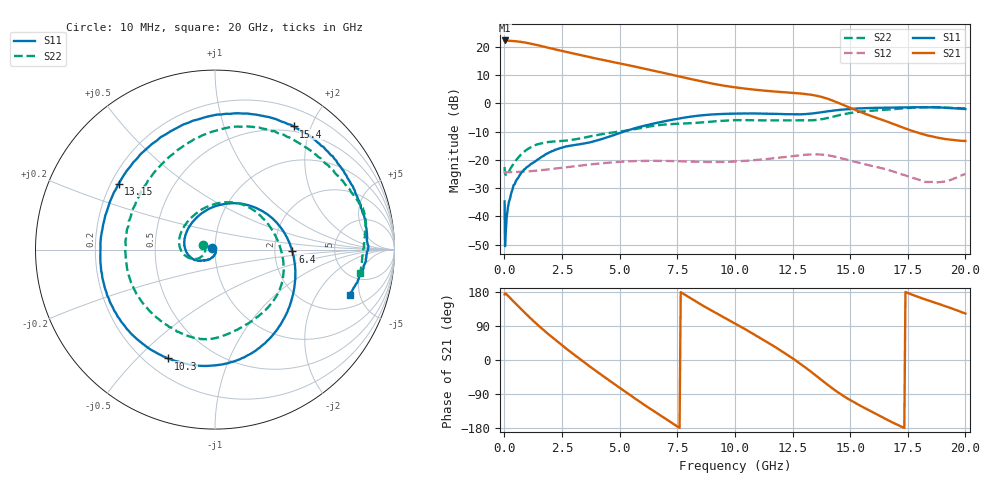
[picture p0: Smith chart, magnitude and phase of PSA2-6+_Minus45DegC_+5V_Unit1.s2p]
!Keysight Technologies,N5242A,MY47200155,A.10.49.08
!Date: Thursday, October 19, 2023 15:29:46
!Correction: S11(Full 2 Port(1,2))
!S21(Full 2 Port(1,2))
!S12(Full 2 Port(1,2))
!S22(Full 2 Port(1,2))
!S2P File: Measurements: S11, S21, S12, S22:
# Hz S  dB  R 50
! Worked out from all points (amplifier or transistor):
!   408 points, 10 MHz to 20 GHz, reference 50 ohm
!   highest |S21| = 22.3 dB at 10 MHz (marker M1)
!   |S21| within 3 dB of that: start of sweep to 2.122 GHz
!   unconditionally stable (mu >= 1): start of sweep to end of sweep
!   at 3.05 GHz: K = 1.05, MAG = 18.5 dB, |S12| = -22.3 dB
!   at 9.85 GHz: K = 1.15, MAG = 10.9 dB, |S12| = -20.7 dB
!   at 20 GHz: K = 4.61, MAG = -3.8 dB, |S12| = -25.0 dB
!   S11 on the Smith chart (normalised r, x): 10 MHz: 0.97, +0.01; 6.4 GHz: 2.52, -0.06; 10.3 GHz: 0.29, -0.62; 13.15 GHz: 0.23, +0.29; 15.4 GHz: 0.43, +1.74; 20 GHz: 2.98, -4.02
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1e7  -34.75 155.8  22.28 173.2  -24.80 -4.2  -22.60 157.5
7e7  -43.70 -59.4  22.18 174.6  -24.40 -1.8  -25.25 -174.3
3.5e8  -30.56 -98.5  22.09 157.5  -24.36 -5.4  -22.01 -153.5
7.5e8  -24.39 -118.5  21.71 132.9  -24.24 -11.7  -17.92 -155.6
1.3e9  -20.79 -138.6  20.87 100.7  -23.90 -21.0  -14.91 -172.9
1.8e9  -17.98 -152.3  19.89 73.9  -23.49 -30.1  -13.84 169.3
2.3e9  -16.18 -171.2  18.93 48.7  -23.01 -39.8  -13.42 148.9
2.8e9  -15.06 166.8  17.99 24.5  -22.53 -50.6  -13.07 126.0
3.35e9  -14.38 139.9  16.99 -1.1  -21.99 -63.4  -12.33 101.3
4.05e9  -13.09 104.6  15.74 -32.3  -21.37 -80.9  -11.20 73.2
4.75e9  -11.22 70.1  14.55 -62.6  -20.86 -99.5  -10.26 46.1
5.5e9  -9.22 36.2  13.30 -94.5  -20.50 -120.2  -9.35 16.5
6.4e9  -7.30 -1.3  11.71 -131.7  -20.36 -145.0  -8.06 -14.6
6.7e9  -6.77 -13.2  11.16 -143.8  -20.37 -153.2  -7.71 -23.3
8.35e9  -4.43 -65.6  8.14 152.9  -20.68 164.1  -6.90 -67.5
1.005e10  -3.64 -107.1  5.62 94.6  -20.53 125.9  -5.97 -97.8
1.03e10  -3.60 -113.4  5.37 86.2  -20.44 120.1  -5.92 -101.8
1.315e10  -3.73 145.6  3.22 -23.8  -18.16 38.9  -6.00 174.8
1.335e10  -3.60 135.6  2.98 -33.3  -18.12 31.2  -6.02 164.5
1.54e10  -1.78 57.4  -2.92 -119.2  -21.09 -40.6  -2.98 75.3
1.67e10  -1.53 30.4  -6.75 -160.6  -23.70 -74.6  -2.18 39.3
2e10  -2.02 -18.5  -13.32 122.6  -24.97 -108.5  -1.75 -9.3
